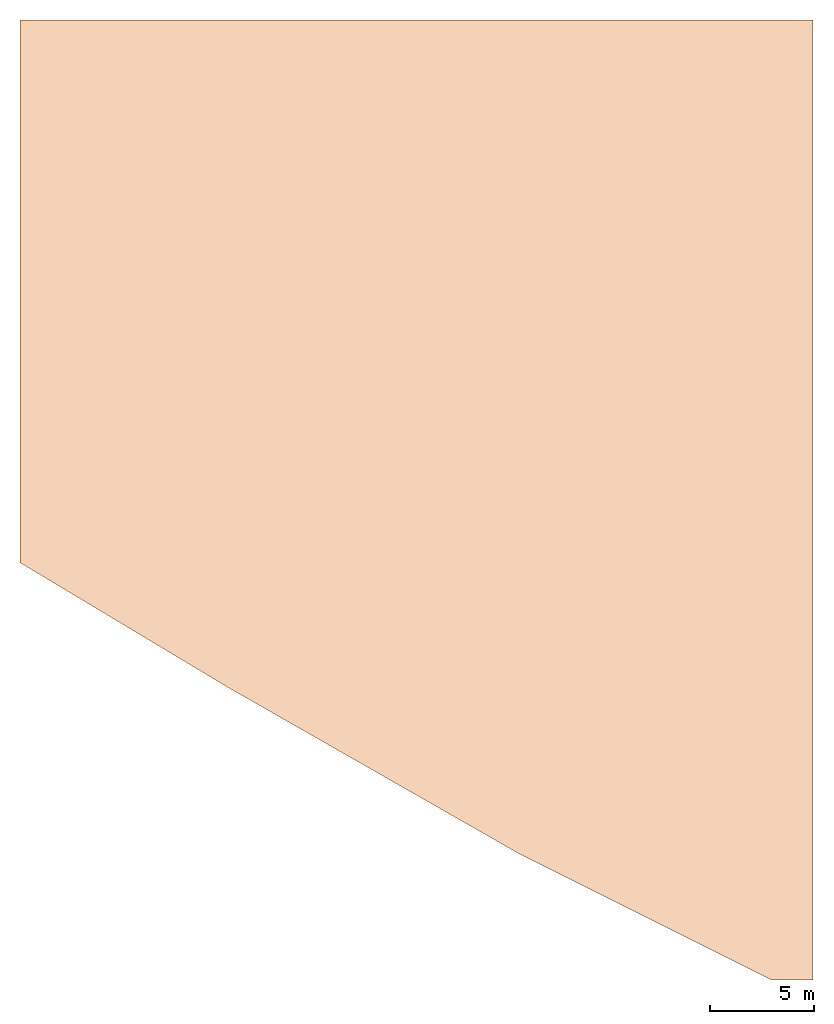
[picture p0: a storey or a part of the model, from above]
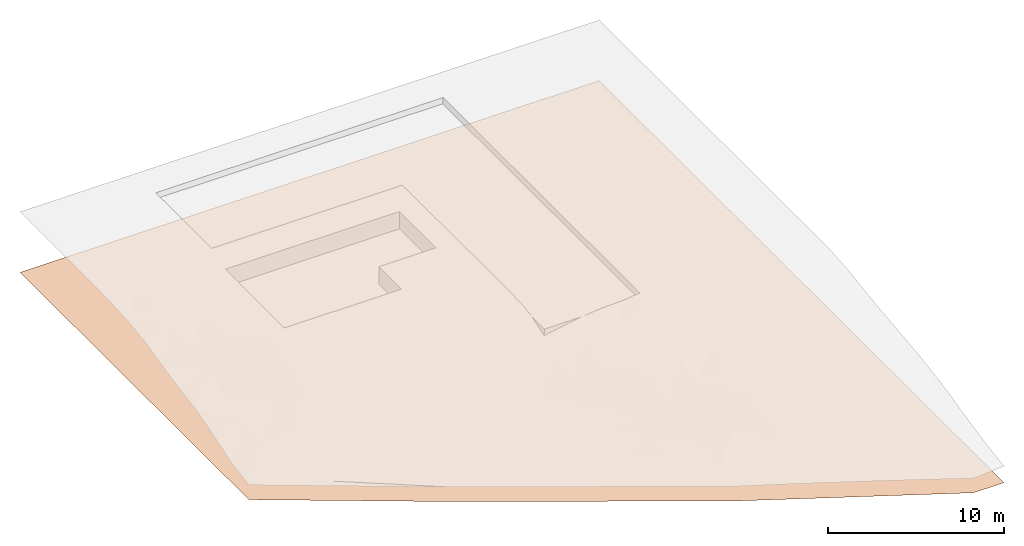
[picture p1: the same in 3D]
Properties of the parts of a building model (IFC4X3_ADD2)

# File
Description: ViewDefinition [CoordinationView_V2.0], ExchangeRequirement [Architecture], Option [IfcExportBaseQuantities: Off], Option [IfcExportElementOnOffAndFrozenLayers: On], Option [IfcExplodeExternalReferences: Off], Option [IfcTesselateBSplineCurvesAndSurfaces: Off], Option [IfcExportSweptSolidAsBRep: Off], Option [IfcExportProfileCenterOfGravity: Off], Option [IfcExportMultiPlyElementsAsAggregated: Off], Option [IfcExportTesselation: 0.000000], Option [IfcCreateUniqueGuidForBlocks: On], Option [IfcCreateUniqueGuidForXrefs: On], Option [IfcExportSubtractOpenings: Off]
File name: /Volumes/ZENTRALE/PROJEKT/TESTS/BLENDER/POOL HOUSE/US_POOL_HOUSE_BRICSCAD_IFC.ifc
Time: 2025-03-28T19:48:41
Author: Undefined
Organization: Undefined
Written by: BricsCAD BIM 25.2.04
Made in: BricsCAD BIM 25.2.04
Authorization: Undefined

# IfcSite, Site
RefLatitude: 0, 0, 0, 0; RefLongitude: 0, 0, 0, 0; RefElevation: 0 m

# IfcBuilding, Default Building
ElevationOfRefHeight: 0 m; ElevationOfTerrain: 0 m

# IfcBuildingStorey, Gruendung
In: Default Building
Elevation: -0.08 m

# IfcSpace: Full-floor, Space
In: Gruendung
LongName: Geschoss EG; PredefinedType: SPACE
Pset_SpaceCommon - GrossPlannedArea: 0 m2; NetPlannedArea: 0 m2
Pset_SpaceCoveringRequirements - FloorCovering: [B011] Linoleum; WallCovering: [S001] Putz; CeilingCovering: [D001] Putz; SkirtingBoard: [L000] Keine
Pset_SpaceOccupancyRequirements - OccupancyNumber: 0; OccupancyNumberPeak: 0; OccupancyTimePerDay: 0 s; AreaPerOccupant: 0 m2; MinimumHeadroom: 0 m

# IfcSpace: Normal (9)
In: Gruendung
PredefinedType: SPACE
Pset_SpaceCommon - GrossPlannedArea: 0 m2; NetPlannedArea: 0 m2
Pset_SpaceCoveringRequirements - FloorCovering: [B021] Betonwerkstein; SkirtingBoard: [L000] Keine
Pset_SpaceOccupancyRequirements - OccupancyNumber: 0; OccupancyNumberPeak: 0; OccupancyTimePerDay: 0 s; AreaPerOccupant: 0 m2; MinimumHeadroom: 0 m
Name | LongName | WallCovering | CeilingCovering
Space | Master Bedroom | [S022] Glas | [D013] Metall
Space | Dressing Room | [S001] Putz | [D020] Abgehängte Bekleidung
Space | Children's Bedroom | [S001] Putz | [D013] Metall
Space | Children's Bathroom | [S001] Putz | [D013] Metall
Space | Kitchen Area | [S022] Glas | [D013] Metall
Space | Service Porch | [S022] Glas | [D013] Metall
Space | Guest Toilet | [S001] Putz | [D020] Abgehängte Bekleidung
Space | Master Bathroom | [S001] Putz | [D020] Abgehängte Bekleidung
Space | Living Room | [S001] Putz | [D013] Metall

# IfcColumn: IfcColumn
In: Gruendung
Material: Default

# IfcColumn: IfcColumn1, IfcColumn
In: Gruendung
Material: Default

# IfcCovering: Default 0 (13)
In: Gruendung
Type - Material: Default

# IfcCovering: Default 0.850534, IfcCovering
In: Gruendung
Type - Material: Default

# IfcCovering: IfcCovering
In: Gruendung
Material: Default

# IfcCovering: IfcCovering1, IfcCovering
In: Gruendung
Material: Default

# IfcCovering: IfcCovering3, IfcCovering
In: Gruendung
Material: Default

# IfcCovering: IfcCovering5, IfcCovering
In: Gruendung
Material: Default

# IfcCovering: IfcCovering7, IfcCovering
In: Gruendung
Material: Default

# IfcDoor (6)
In: Gruendung
Type - ParameterTakesPrecedence: no
OverallHeight: 2.3 m; Material: Default
Pset_DoorCommon - Reference: D-1; Infiltration: 0; IsExternal: no; ThermalTransmittance: 0; HandicapAccessible: no; FireExit: no; SelfClosing: no; SmokeStop: no
Name | OverallWidth (m)
4 x Tr Schieben 76X204 | 0.885
Tr Zarge 88.5x204 | 0.885
Tr Zarge 88.5x204 | 0.635

# IfcFlowTerminal (3)
In: Space
Material: Default

# IfcFooting (10)
In: Gruendung
Material: W-Streifenfundament
Name | PredefinedType
8 x  | STRIP_FOOTING
2 x  | PAD_FOOTING

# IfcFurniture (25)
Material: Default
Name | In | PredefinedType
14 x IfcFurniture | Space | FILECABINET
Shelf | Space | Description: Custom Cabinet - 3x1x2
Shelf | Space | Description: Custom Cabinet - 2x1x2
Table and Chairs | Space | Pset_FurnitureTypeCommon - NominalHeight: 0.75 m; NominalLength: 2500 m; NominalDepth: 1200 m
6 x IfcFurniture | Gruendung | SHELF
2 x IfcFurniture | Gruendung | TECHNICALCABINET

# IfcFurniture: Bett 100x200 ModuQueen (2)
In: Space
PredefinedType: BED; Material: Default

# IfcFurniture: Bett 200x200 ModuQueen, IfcFurniture
In: Space
PredefinedType: BED; Material: Default

# IfcFurniture: Sitzgruppe Corbusier 03, IfcFurniture
In: Space
PredefinedType: SOFA; Material: Default

# IfcFurniture: Sitzgruppe Corbusier 05 (2)
In: Space
PredefinedType: SOFA; Material: Default

# IfcFurniture: Sitzgruppe Jacobsen 01 Ei, IfcFurniture
In: Space
PredefinedType: CHAIR; Material: Default

# IfcFurniture: Sitzgruppe Jacobsen 02 Ei, IfcFurniture
In: Space
PredefinedType: CHAIR; Material: Default

# IfcFurniture: Sprungbrett, IfcFurniture
In: Gruendung
Material: Default

# IfcFurniture: Stuhl Mies 01 Barcelona (2)
In: Space
PredefinedType: CHAIR; Material: Default

# IfcFurniture: Stuhl Mies 03 Barcelona, IfcFurniture
In: Space
PredefinedType: CHAIR; Material: Default

# IfcFurniture: Stuhl Rietvald 01 Z (4)
PredefinedType: CHAIR; Material: Default
Name | In
3 x IfcFurniture | Space
IfcFurniture | Gruendung

# IfcGeographicElement (2)
In: Civil Road
PredefinedType: TERRAIN
Name
Geländemodell
Geländemodell1

# IfcMember: DIN - IPE 300 (4)
In: Gruendung
Material: Default

# IfcMember: HEA 100 (14)
In: Gruendung
Material: Default

# IfcSanitaryTerminal (2)
In: Gruendung
Name
IfcSanitaryTerminal | PredefinedType: BATH; Material: Default


# IfcSlab: Beton 0.2, Bodenaufbau Erdgeschoss CH 36 cm
In: Gruendung
Type - PredefinedType: FLOOR; Material: Beton
Pset_SlabCommon - Reference: Bodenaufbau Erdgeschoss CH 36 cm; Combustible: no; Compartmentation: no; IsExternal: no; ThermalTransmittance: 4; LoadBearing: no

# IfcSlab: Default 0.01, IfcSlab
In: Gruendung
Type - PredefinedType: FLOOR; Material: Default

# IfcSlab: Slab LayerSet, Floor
In: Gruendung
Type - PredefinedType: FLOOR; Material: Concrete

# IfcSlab: Slab LayerSet_2 (3)
In: Gruendung
Type - PredefinedType: FLOOR; Material: Concrete

# IfcSlab: Slab LayerSet_3 (2)
In: Gruendung
Type - PredefinedType: FLOOR; Material: Concrete

# IfcSpaceHeater: Moebiliar-Kamin, IfcSpaceHeater
In: Space
Material: Default

# IfcWall: Aussenwand 15cm 0.15
In: Gruendung
Type - PredefinedType: STANDARD; Material: Aussenwand 15cm

# IfcWall: Gipsständerwand 10 cm
In: Gruendung
Description: Gipsständerwand 10cm, beidseitig doppelt beplankt
Pset_WallCommon - Reference: Gipsständerwand 10cm; Combustible: no; ThermalTransmittance: 5.882; IsExternal: no; LoadBearing: no; Compartmentation: no

# IfcWall: Gipsständerwand 10 cm1, Gipsständerwand 10 cm
In: Gruendung
Description: Gipsständerwand 10cm, beidseitig doppelt beplankt
Pset_WallCommon - Reference: Gipsständerwand 10cm; Combustible: no; ThermalTransmittance: 5.882; IsExternal: no; LoadBearing: no; Compartmentation: no

# IfcWall: Gipsständerwand 10 cm11, Gipsständerwand 10 cm
In: Gruendung
Description: Gipsständerwand 10cm, beidseitig doppelt beplankt
Pset_WallCommon - Reference: Gipsständerwand 10cm; Combustible: no; ThermalTransmittance: 5.882; IsExternal: no; LoadBearing: no; Compartmentation: no

# IfcWall: Gipsständerwand 10 cm13 (2)
In: Gruendung
Description: Gipsständerwand 10cm, beidseitig doppelt beplankt
Pset_WallCommon - Reference: Gipsständerwand 10cm; Combustible: no; ThermalTransmittance: 5.882; IsExternal: no; LoadBearing: no; Compartmentation: no

# IfcWall: Gipsständerwand 10 cm15, Gipsständerwand 10 cm
In: Gruendung
Description: Gipsständerwand 10cm, beidseitig doppelt beplankt
Pset_WallCommon - Reference: Gipsständerwand 10cm; Combustible: no; ThermalTransmittance: 5.882; IsExternal: no; LoadBearing: no; Compartmentation: no

# IfcWall: Gipsständerwand 10 cm17, Gipsständerwand 10 cm
In: Gruendung
Description: Gipsständerwand 10cm, beidseitig doppelt beplankt
Pset_WallCommon - Reference: Gipsständerwand 10cm; Combustible: no; ThermalTransmittance: 5.882; IsExternal: no; LoadBearing: no; Compartmentation: no

# IfcWall: Gipsständerwand 10 cm3, Gipsständerwand 10 cm
In: Gruendung
Description: Gipsständerwand 10cm, beidseitig doppelt beplankt
Pset_WallCommon - Reference: Gipsständerwand 10cm; Combustible: no; ThermalTransmittance: 5.882; IsExternal: no; LoadBearing: no; Compartmentation: no

# IfcWall: Gipsständerwand 10 cm5, Gipsständerwand 10 cm
In: Gruendung
Description: Gipsständerwand 10cm, beidseitig doppelt beplankt
Pset_WallCommon - Reference: Gipsständerwand 10cm; Combustible: no; ThermalTransmittance: 5.882; IsExternal: no; LoadBearing: no; Compartmentation: no

# IfcWall: Gipsständerwand 10 cm7, Gipsständerwand 10 cm
In: Gruendung
Description: Gipsständerwand 10cm, beidseitig doppelt beplankt
Pset_WallCommon - Reference: Gipsständerwand 10cm; Combustible: no; ThermalTransmittance: 5.882; IsExternal: no; LoadBearing: no; Compartmentation: no

# IfcWall: Gipsständerwand 15 cm
In: Gruendung
Description: Gipsständerwand 15cm, beidseitig doppelt beplankt
Pset_WallCommon - Reference: Gipsständerwand 15cm; Combustible: no; ThermalTransmittance: 5.882; IsExternal: no; LoadBearing: no; Compartmentation: no

# IfcWall: Gipsständerwand 15 cm1, Gipsständerwand 15 cm
In: Gruendung
Description: Gipsständerwand 15cm, beidseitig doppelt beplankt
Pset_WallCommon - Reference: Gipsständerwand 15cm; Combustible: no; ThermalTransmittance: 5.882; IsExternal: no; LoadBearing: no; Compartmentation: no

# IfcWall: Gipsständerwand 15 cm11, Gipsständerwand 15 cm
In: Gruendung
Description: Gipsständerwand 15cm, beidseitig doppelt beplankt
Pset_WallCommon - Reference: Gipsständerwand 15cm; Combustible: no; ThermalTransmittance: 5.882; IsExternal: no; LoadBearing: no; Compartmentation: no

# IfcWall: Gipsständerwand 15 cm13, Gipsständerwand 15 cm
In: Gruendung
Description: Gipsständerwand 15cm, beidseitig doppelt beplankt
Pset_WallCommon - Reference: Gipsständerwand 15cm; Combustible: no; ThermalTransmittance: 5.882; IsExternal: no; LoadBearing: no; Compartmentation: no

# IfcWall: Gipsständerwand 15 cm15, Gipsständerwand 15 cm
In: Gruendung
Description: Gipsständerwand 15cm, beidseitig doppelt beplankt
Pset_WallCommon - Reference: Gipsständerwand 15cm; Combustible: no; ThermalTransmittance: 5.882; IsExternal: no; LoadBearing: no; Compartmentation: no

# IfcWall: Gipsständerwand 15 cm17, Gipsständerwand 15 cm
In: Gruendung
Description: Gipsständerwand 15cm, beidseitig doppelt beplankt
Pset_WallCommon - Reference: Gipsständerwand 15cm; Combustible: no; ThermalTransmittance: 5.882; IsExternal: no; LoadBearing: no; Compartmentation: no

# IfcWall: Gipsständerwand 15 cm3, Gipsständerwand 15 cm
In: Gruendung
Description: Gipsständerwand 15cm, beidseitig doppelt beplankt
Pset_WallCommon - Reference: Gipsständerwand 15cm; Combustible: no; ThermalTransmittance: 5.882; IsExternal: no; LoadBearing: no; Compartmentation: no

# IfcWall: Gipsständerwand 15 cm5, Gipsständerwand 15 cm
In: Gruendung
Description: Gipsständerwand 15cm, beidseitig doppelt beplankt
Pset_WallCommon - Reference: Gipsständerwand 15cm; Combustible: no; ThermalTransmittance: 5.882; IsExternal: no; LoadBearing: no; Compartmentation: no

# IfcWall: Gipsständerwand 15 cm7, Gipsständerwand 15 cm
In: Gruendung
Description: Gipsständerwand 15cm, beidseitig doppelt beplankt
Pset_WallCommon - Reference: Gipsständerwand 15cm; Combustible: no; ThermalTransmittance: 5.882; IsExternal: no; LoadBearing: no; Compartmentation: no

# IfcWall: Gipsständerwand 15 cm9, Gipsständerwand 15 cm
In: Gruendung
Description: Gipsständerwand 15cm, beidseitig doppelt beplankt
Pset_WallCommon - Reference: Gipsständerwand 15cm; Combustible: no; ThermalTransmittance: 5.882; IsExternal: no; LoadBearing: no; Compartmentation: no

# IfcWall: Glas 0.039999 (3)
In: Gruendung
Type - PredefinedType: STANDARD; Material: Glas
Pset_WallCommon - Reference: Glaswand; Combustible: no; ThermalTransmittance: 5.882; IsExternal: no; LoadBearing: no; Compartmentation: no

# IfcWall: W-CASE 20
In: Gruendung
Description: Case_study Aussenwand Trapezblech auf Ständerwerk
Pset_WallCommon - Reference: Aussenwand; Combustible: no; ThermalTransmittance: 0.283; IsExternal: yes; LoadBearing: no; Compartmentation: no

# IfcWall: W-CASE 20_1, W-CASE 20
In: Gruendung
Description: Case_study Aussenwand Trapezblech auf Ständerwerk
Pset_WallCommon - Reference: Aussenwand; Combustible: no; ThermalTransmittance: 0.283; IsExternal: yes; LoadBearing: no; Compartmentation: no

# IfcWall: W-CASE 20_3, W-CASE 20
In: Gruendung
Description: Case_study Aussenwand Trapezblech auf Ständerwerk
Pset_WallCommon - Reference: Aussenwand; Combustible: no; ThermalTransmittance: 0.283; IsExternal: yes; LoadBearing: no; Compartmentation: no

# IfcWall: W-CASE 20_5, W-CASE 20
In: Gruendung
Description: Case_study Aussenwand Trapezblech auf Ständerwerk
Pset_WallCommon - Reference: Aussenwand; Combustible: no; ThermalTransmittance: 0.283; IsExternal: yes; LoadBearing: no; Compartmentation: no

# IfcWall: W-CASE Trapez
In: Gruendung
Description: Case_study Aussenwand Trapezblech auf Ständerwerk
Pset_WallCommon - Reference: Aussenwand; Combustible: no; ThermalTransmittance: 0.29; IsExternal: yes; LoadBearing: no; Compartmentation: no

# IfcWall: W-CASE Trapez1, W-CASE Trapez
In: Gruendung
Description: Case_study Aussenwand Trapezblech auf Ständerwerk
Pset_WallCommon - Reference: Aussenwand; Combustible: no; ThermalTransmittance: 0.29; IsExternal: yes; LoadBearing: no; Compartmentation: no

# IfcWall: W-CASE Trapez3, W-CASE Trapez
In: Gruendung
Description: Case_study Aussenwand Trapezblech auf Ständerwerk
Pset_WallCommon - Reference: Aussenwand; Combustible: no; ThermalTransmittance: 0.29; IsExternal: yes; LoadBearing: no; Compartmentation: no

# IfcWindow (10)
In: Gruendung
Type - ParameterTakesPrecedence: no
Material: Default
Pset_WindowCommon - Reference: W-1; IsExternal: no; Infiltration: 0; SmokeStop: no; FireExit: no
Name | ThermalTransmittance | GlazingAreaFraction
Fe Stumpf 2FlgS 2Gl Eckig | 0 | 0.712329
4 x Fe Stumpf 2FlgS 2Gl Eckig | 2.83487 | 0.871871
2 x Fe Stumpf 2FlgS 2Gl Eckig | 2.83384 | 0.841418
Fe Stumpf 2FlgS 2Gl Eckig | 2.83605 | 0.867956
Fe Stumpf 2FlgS 2Gl Eckig | 0 | 0.871871
Fe Stumpf 2FlgS 2Gl Eckig | 2.82724 | 0.880445
